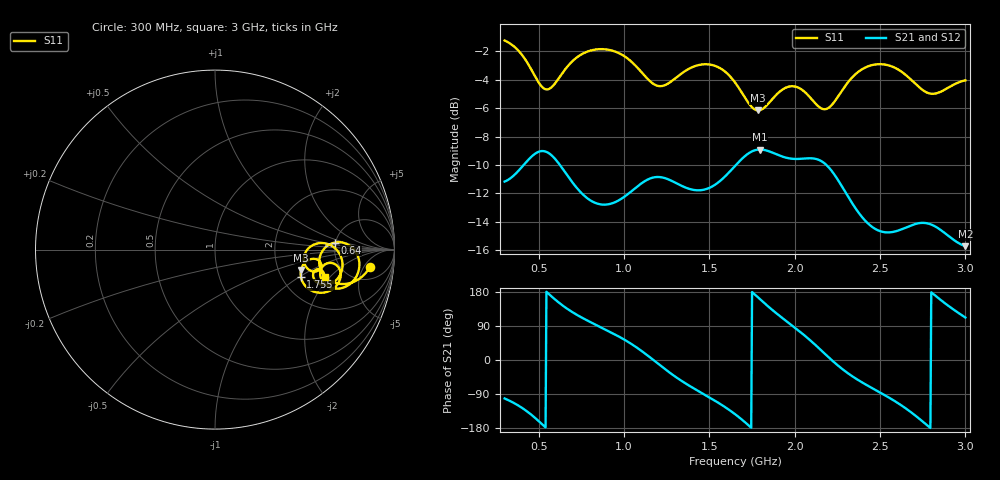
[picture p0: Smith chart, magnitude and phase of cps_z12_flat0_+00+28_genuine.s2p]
! cps_z12_flat0_+00+28_genuine
! simulated by sim/fixtures_fdtd.py (S12 = S21, S22 not computed)
# HZ S RI R 50
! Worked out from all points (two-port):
!   541 points, 300 MHz to 3 GHz, reference 50 ohm
!   highest |S21| = -8.90 dB at 1.795 GHz (marker M1); lowest = -15.7 dB at 3 GHz (marker M2)
!   |S21| within 3 dB of the highest: start of sweep to 744.9 MHz; 1.037 GHz to 2.297 GHz (1.259 GHz wide, 75.6 % of centre)
!   lowest |S11| = -6.2 dB at 1.785 GHz (marker M3), VSWR 2.94, Z = 133 - j40 ohm
!   |S11| at or under -10 dB: nowhere
!   |S22| runs from - to - dB; largest |S21 - S12| = 0
!   S11 on the Smith chart (normalised r, x): 300 MHz: 9, -7; 640 MHz: 4.93, +0.70; 1.755 GHz: 2.54, -1.03; 3 GHz: 3.47, -1.72
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3e8  0.8633 -0.0968  -0.0552 -0.271  -0.0552 -0.271  0 0
4.2e8  0.7211 -0.1917  -0.214 -0.2386  -0.214 -0.2386  0 0
5.15e8  0.5893 -0.113  -0.3457 -0.0765  -0.3457 -0.0765  0 0
6.4e8  0.6672 0.0392  -0.2476 0.1813  -0.2476 0.1813  0 0
7.5e8  0.7758 -0.000915  -0.0962 0.233  -0.0962 0.233  0 0
8.9e8  0.7993 -0.1211  0.0378 0.2262  0.0378 0.2262  0 0
1.03e9  0.7115 -0.2129  0.1751 0.1811  0.1751 0.1811  0 0
1.2e9  0.5858 -0.1321  0.2826 -0.0505  0.2826 -0.0505  0 0
1.395e9  0.6899 -0.1015  0.0829 -0.2457  0.0829 -0.2457  0 0
1.52e9  0.685 -0.1903  -0.0649 -0.2585  -0.0649 -0.2585  0 0
1.65e9  0.5701 -0.2391  -0.2502 -0.1895  -0.2502 -0.1895  0 0
1.755e9  0.4785 -0.1515  -0.3541 0.0166  -0.3541 0.0166  0 0
1.785e9  0.4791 -0.1137  -0.3463 0.0923  -0.3463 0.0923  0 0
1.795e9  0.4825 -0.102  -0.3392 0.1168  -0.3392 0.1168  0 0
1.94e9  0.5854 -0.0679  -0.095 0.3232  -0.095 0.3232  0 0
2.1e9  0.5264 -0.1147  0.2223 0.2492  0.2223 0.2492  0 0
2.19e9  0.4988 -0.0284  0.309 0.0586  0.309 0.0586  0 0
2.3e9  0.6044 0.0361  0.2157 -0.1302  0.2157 -0.1302  0 0
2.425e9  0.7014 -0.0385  0.0772 -0.1823  0.0772 -0.1823  0 0
2.55e9  0.6946 -0.1453  -0.0275 -0.181  -0.0275 -0.181  0 0
2.78e9  0.5472 -0.1508  -0.1957 -0.0214  -0.1957 -0.0214  0 0
3e9  0.6102 -0.1499  -0.0615 0.1518  -0.0615 0.1518  0 0
